VERSION 5.7 ;
  NOWIREEXTENSIONATPIN ON ;
  DIVIDERCHAR "/" ;
  BUSBITCHARS "[]" ;
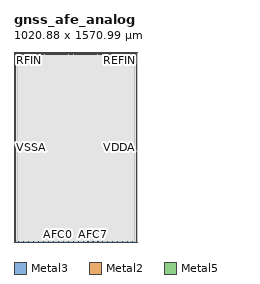
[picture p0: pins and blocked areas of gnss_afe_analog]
MACRO gnss_afe_analog
  CLASS BLOCK ;
  FOREIGN gnss_afe_analog ;
  ORIGIN 0.000 0.000 ;
  SIZE 1020.880 BY 1570.995 ;
  PIN VSSA
    DIRECTION INOUT ;
    USE GROUND ;
    PORT
      LAYER Metal3 ;
        RECT 6.000 6.000 9.000 1564.995 ;
    END
    PORT
      LAYER Metal2 ;
        RECT 431.640 1564.895 441.140 1570.995 ;
    END
    PORT
      LAYER Metal2 ;
        RECT 418.490 1564.895 428.740 1570.995 ;
    END
    PORT
      LAYER Metal2 ;
        RECT 406.640 1564.895 416.890 1570.995 ;
    END
    PORT
      LAYER Metal2 ;
        RECT 393.110 1564.895 403.360 1570.995 ;
    END
    PORT
      LAYER Metal2 ;
        RECT 381.260 1564.895 391.510 1570.995 ;
    END
    PORT
      LAYER Metal2 ;
        RECT 368.860 1564.895 378.360 1570.995 ;
    END
    PORT
      LAYER Metal2 ;
        RECT 223.640 1564.895 233.140 1570.995 ;
    END
    PORT
      LAYER Metal2 ;
        RECT 210.490 1564.895 220.740 1570.995 ;
    END
    PORT
      LAYER Metal2 ;
        RECT 198.640 1564.895 208.890 1570.995 ;
    END
    PORT
      LAYER Metal2 ;
        RECT 185.110 1564.895 195.360 1570.995 ;
    END
    PORT
      LAYER Metal2 ;
        RECT 173.260 1564.895 183.510 1570.995 ;
    END
    PORT
      LAYER Metal2 ;
        RECT 160.860 1564.895 170.360 1570.995 ;
    END
    PORT
      LAYER Metal2 ;
        RECT 15.640 1564.895 25.140 1570.995 ;
    END
    PORT
      LAYER Metal2 ;
        RECT 6.500 1564.895 12.740 1570.995 ;
    END
    PORT
      LAYER Metal5 ;
        RECT 6.000 1560.995 1014.880 1564.995 ;
    END
  END VSSA
  PIN VDDA
    DIRECTION INOUT ;
    USE POWER ;
    PORT
      LAYER Metal3 ;
        RECT 1011.880 6.000 1014.880 1564.995 ;
    END
    PORT
      LAYER Metal2 ;
        RECT 327.640 1553.895 337.140 1570.995 ;
    END
    PORT
      LAYER Metal2 ;
        RECT 314.490 1553.895 324.740 1570.995 ;
    END
    PORT
      LAYER Metal2 ;
        RECT 302.640 1553.895 312.890 1570.995 ;
    END
    PORT
      LAYER Metal2 ;
        RECT 289.110 1553.895 299.360 1570.995 ;
    END
    PORT
      LAYER Metal2 ;
        RECT 277.260 1553.895 287.510 1570.995 ;
    END
    PORT
      LAYER Metal2 ;
        RECT 264.860 1553.895 274.360 1570.995 ;
    END
    PORT
      LAYER Metal5 ;
        RECT 6.000 1549.995 45.500 1553.995 ;
    END
    PORT
      LAYER Metal5 ;
        RECT 56.500 1549.995 85.500 1553.995 ;
    END
    PORT
      LAYER Metal5 ;
        RECT 96.500 1549.995 125.500 1553.995 ;
    END
    PORT
      LAYER Metal5 ;
        RECT 136.500 1549.995 165.500 1553.995 ;
    END
    PORT
      LAYER Metal5 ;
        RECT 176.500 1549.995 205.500 1553.995 ;
    END
    PORT
      LAYER Metal5 ;
        RECT 216.500 1549.995 245.500 1553.995 ;
    END
    PORT
      LAYER Metal5 ;
        RECT 256.500 1549.995 285.500 1553.995 ;
    END
    PORT
      LAYER Metal5 ;
        RECT 296.500 1549.995 325.500 1553.995 ;
    END
    PORT
      LAYER Metal5 ;
        RECT 336.500 1549.995 365.500 1553.995 ;
    END
    PORT
      LAYER Metal5 ;
        RECT 376.500 1549.995 405.500 1553.995 ;
    END
    PORT
      LAYER Metal5 ;
        RECT 416.500 1549.995 445.500 1553.995 ;
    END
    PORT
      LAYER Metal5 ;
        RECT 456.500 1549.995 485.500 1553.995 ;
    END
    PORT
      LAYER Metal5 ;
        RECT 496.500 1549.995 525.500 1553.995 ;
    END
    PORT
      LAYER Metal5 ;
        RECT 536.500 1549.995 565.500 1553.995 ;
    END
    PORT
      LAYER Metal5 ;
        RECT 576.500 1549.995 605.500 1553.995 ;
    END
    PORT
      LAYER Metal5 ;
        RECT 616.500 1549.995 645.500 1553.995 ;
    END
    PORT
      LAYER Metal5 ;
        RECT 656.500 1549.995 665.500 1553.995 ;
    END
    PORT
      LAYER Metal5 ;
        RECT 676.500 1549.995 685.500 1553.995 ;
    END
    PORT
      LAYER Metal5 ;
        RECT 696.500 1549.995 725.500 1553.995 ;
    END
    PORT
      LAYER Metal5 ;
        RECT 736.500 1549.995 745.500 1553.995 ;
    END
    PORT
      LAYER Metal5 ;
        RECT 756.500 1549.995 765.500 1553.995 ;
    END
    PORT
      LAYER Metal5 ;
        RECT 776.500 1549.995 805.500 1553.995 ;
    END
    PORT
      LAYER Metal5 ;
        RECT 816.500 1549.995 825.500 1553.995 ;
    END
    PORT
      LAYER Metal5 ;
        RECT 836.500 1549.995 845.500 1553.995 ;
    END
    PORT
      LAYER Metal5 ;
        RECT 856.500 1549.995 885.500 1553.995 ;
    END
    PORT
      LAYER Metal5 ;
        RECT 896.500 1549.995 905.500 1553.995 ;
    END
    PORT
      LAYER Metal5 ;
        RECT 916.500 1549.995 925.500 1553.995 ;
    END
    PORT
      LAYER Metal5 ;
        RECT 936.500 1549.995 965.500 1553.995 ;
    END
    PORT
      LAYER Metal5 ;
        RECT 976.500 1549.995 1014.880 1553.995 ;
    END
  END VDDA
  PIN RFIN
    DIRECTION INOUT ;
    USE SIGNAL ;
    ANTENNADIFFAREA 33.599998 ;
    PORT
      LAYER Metal2 ;
        RECT 70.840 1568.995 115.160 1570.995 ;
    END
  END RFIN
  PIN VDDV
    DIRECTION INOUT ;
    USE POWER ;
    PORT
      LAYER Metal2 ;
        RECT 535.640 1559.395 545.140 1570.995 ;
    END
    PORT
      LAYER Metal2 ;
        RECT 522.490 1559.395 532.740 1570.995 ;
    END
    PORT
      LAYER Metal2 ;
        RECT 510.640 1559.395 520.890 1570.995 ;
    END
    PORT
      LAYER Metal2 ;
        RECT 497.110 1559.395 507.360 1570.995 ;
    END
    PORT
      LAYER Metal2 ;
        RECT 485.260 1559.395 495.510 1570.995 ;
    END
    PORT
      LAYER Metal2 ;
        RECT 472.860 1559.395 482.360 1570.995 ;
    END
    PORT
      LAYER Metal5 ;
        RECT 6.000 1555.495 45.500 1559.495 ;
    END
    PORT
      LAYER Metal5 ;
        RECT 56.500 1555.495 85.500 1559.495 ;
    END
    PORT
      LAYER Metal5 ;
        RECT 96.500 1555.495 125.500 1559.495 ;
    END
    PORT
      LAYER Metal5 ;
        RECT 136.500 1555.495 165.500 1559.495 ;
    END
    PORT
      LAYER Metal5 ;
        RECT 176.500 1555.495 205.500 1559.495 ;
    END
    PORT
      LAYER Metal5 ;
        RECT 216.500 1555.495 245.500 1559.495 ;
    END
    PORT
      LAYER Metal5 ;
        RECT 256.500 1555.495 285.500 1559.495 ;
    END
    PORT
      LAYER Metal5 ;
        RECT 296.500 1555.495 325.500 1559.495 ;
    END
    PORT
      LAYER Metal5 ;
        RECT 336.500 1555.495 365.500 1559.495 ;
    END
    PORT
      LAYER Metal5 ;
        RECT 376.500 1555.495 405.500 1559.495 ;
    END
    PORT
      LAYER Metal5 ;
        RECT 416.500 1555.495 445.500 1559.495 ;
    END
    PORT
      LAYER Metal5 ;
        RECT 456.500 1555.495 485.500 1559.495 ;
    END
    PORT
      LAYER Metal5 ;
        RECT 496.500 1555.495 525.500 1559.495 ;
    END
    PORT
      LAYER Metal5 ;
        RECT 536.500 1555.495 565.500 1559.495 ;
    END
    PORT
      LAYER Metal5 ;
        RECT 576.500 1555.495 605.500 1559.495 ;
    END
    PORT
      LAYER Metal5 ;
        RECT 616.500 1555.495 645.500 1559.495 ;
    END
    PORT
      LAYER Metal5 ;
        RECT 656.500 1555.495 685.500 1559.495 ;
    END
    PORT
      LAYER Metal5 ;
        RECT 696.500 1555.495 725.500 1559.495 ;
    END
    PORT
      LAYER Metal5 ;
        RECT 736.500 1555.495 765.500 1559.495 ;
    END
    PORT
      LAYER Metal5 ;
        RECT 776.500 1555.495 805.500 1559.495 ;
    END
    PORT
      LAYER Metal5 ;
        RECT 816.500 1555.495 845.500 1559.495 ;
    END
    PORT
      LAYER Metal5 ;
        RECT 856.500 1555.495 885.500 1559.495 ;
    END
    PORT
      LAYER Metal5 ;
        RECT 896.500 1555.495 925.500 1559.495 ;
    END
    PORT
      LAYER Metal5 ;
        RECT 936.500 1555.495 965.500 1559.495 ;
    END
    PORT
      LAYER Metal5 ;
        RECT 976.500 1555.495 1014.880 1559.495 ;
    END
  END VDDV
  PIN REFIN
    DIRECTION INOUT ;
    USE SIGNAL ;
    PORT
      LAYER Metal2 ;
        RECT 1011.500 1568.995 1019.880 1570.995 ;
    END
  END REFIN
  PIN AFCOUT
    DIRECTION INOUT ;
    USE SIGNAL ;
    PORT
      LAYER Metal2 ;
        RECT 915.000 1568.995 925.000 1570.995 ;
    END
  END AFCOUT
  PIN VCTRL
    DIRECTION INOUT ;
    USE SIGNAL ;
    PORT
      LAYER Metal2 ;
        RECT 603.000 1568.995 613.000 1570.995 ;
    END
  END VCTRL
  PIN IG1A
    DIRECTION INOUT ;
    USE SIGNAL ;
    ANTENNAGATEAREA 22.719999 ;
    PORT
      LAYER Metal3 ;
        RECT 39.800 -0.100 40.800 0.900 ;
    END
  END IG1A
  PIN IG1B
    DIRECTION INOUT ;
    USE SIGNAL ;
    ANTENNAGATEAREA 22.719999 ;
    PORT
      LAYER Metal3 ;
        RECT 80.400 -0.100 81.400 0.900 ;
    END
  END IG1B
  PIN IG2A
    DIRECTION INOUT ;
    USE SIGNAL ;
    ANTENNAGATEAREA 22.719999 ;
    PORT
      LAYER Metal3 ;
        RECT 121.700 -0.100 122.700 0.900 ;
    END
  END IG2A
  PIN IG2B
    DIRECTION INOUT ;
    USE SIGNAL ;
    ANTENNAGATEAREA 22.719999 ;
    PORT
      LAYER Metal3 ;
        RECT 162.300 -0.100 163.300 0.900 ;
    END
  END IG2B
  PIN IG3A
    DIRECTION INOUT ;
    USE SIGNAL ;
    ANTENNAGATEAREA 22.719999 ;
    PORT
      LAYER Metal3 ;
        RECT 202.900 -0.100 203.900 0.900 ;
    END
  END IG3A
  PIN IG3B
    DIRECTION INOUT ;
    USE SIGNAL ;
    ANTENNAGATEAREA 22.719999 ;
    PORT
      LAYER Metal3 ;
        RECT 244.200 -0.100 245.200 0.900 ;
    END
  END IG3B
  PIN B0
    DIRECTION INOUT ;
    USE SIGNAL ;
    PORT
      LAYER Metal3 ;
        RECT 284.800 -0.100 285.800 0.900 ;
    END
  END B0
  PIN B1
    DIRECTION INOUT ;
    USE SIGNAL ;
    PORT
      LAYER Metal3 ;
        RECT 325.400 -0.100 326.400 0.900 ;
    END
  END B1
  PIN AFC0
    DIRECTION INOUT ;
    USE SIGNAL ;
    ANTENNAGATEAREA 0.840000 ;
    PORT
      LAYER Metal3 ;
        RECT 366.700 -0.100 367.700 0.900 ;
    END
  END AFC0
  PIN AFC1
    DIRECTION INOUT ;
    USE SIGNAL ;
    ANTENNAGATEAREA 0.840000 ;
    PORT
      LAYER Metal3 ;
        RECT 407.300 -0.100 408.300 0.900 ;
    END
  END AFC1
  PIN AFC2
    DIRECTION INOUT ;
    USE SIGNAL ;
    ANTENNAGATEAREA 0.840000 ;
    PORT
      LAYER Metal3 ;
        RECT 447.900 -0.100 448.900 0.900 ;
    END
  END AFC2
  PIN AFC3
    DIRECTION INOUT ;
    USE SIGNAL ;
    ANTENNAGATEAREA 0.840000 ;
    PORT
      LAYER Metal3 ;
        RECT 489.200 -0.100 490.200 0.900 ;
    END
  END AFC3
  PIN AFC4
    DIRECTION INOUT ;
    USE SIGNAL ;
    ANTENNAGATEAREA 0.840000 ;
    PORT
      LAYER Metal3 ;
        RECT 529.800 -0.100 530.800 0.900 ;
    END
  END AFC4
  PIN AFC5
    DIRECTION INOUT ;
    USE SIGNAL ;
    ANTENNAGATEAREA 0.840000 ;
    PORT
      LAYER Metal3 ;
        RECT 571.100 -0.100 572.100 0.900 ;
    END
  END AFC5
  PIN AFC6
    DIRECTION INOUT ;
    USE SIGNAL ;
    ANTENNAGATEAREA 0.840000 ;
    PORT
      LAYER Metal3 ;
        RECT 611.700 -0.100 612.700 0.900 ;
    END
  END AFC6
  PIN AFC7
    DIRECTION INOUT ;
    USE SIGNAL ;
    ANTENNAGATEAREA 0.840000 ;
    PORT
      LAYER Metal3 ;
        RECT 652.300 -0.100 653.300 0.900 ;
    END
  END AFC7
  PIN ICP2
    DIRECTION INOUT ;
    USE SIGNAL ;
    ANTENNAGATEAREA 1.960000 ;
    PORT
      LAYER Metal3 ;
        RECT 693.600 -0.100 694.600 0.900 ;
    END
  END ICP2
  PIN BWK
    DIRECTION INOUT ;
    USE SIGNAL ;
    ANTENNAGATEAREA 0.840000 ;
    ANTENNADIFFAREA 0.445000 ;
    PORT
      LAYER Metal3 ;
        RECT 734.200 -0.100 735.200 0.900 ;
    END
  END BWK
  PIN BWN
    DIRECTION INOUT ;
    USE SIGNAL ;
    ANTENNAGATEAREA 0.840000 ;
    ANTENNADIFFAREA 0.445000 ;
    PORT
      LAYER Metal3 ;
        RECT 774.800 -0.100 775.800 0.900 ;
    END
  END BWN
  PIN I_SIGN
    DIRECTION INOUT ;
    USE SIGNAL ;
    ANTENNAGATEAREA 1.400000 ;
    ANTENNADIFFAREA 2.670000 ;
    PORT
      LAYER Metal3 ;
        RECT 816.100 -0.100 817.100 0.900 ;
    END
  END I_SIGN
  PIN I_MAG
    DIRECTION INOUT ;
    USE SIGNAL ;
    ANTENNADIFFAREA 2.670000 ;
    PORT
      LAYER Metal3 ;
        RECT 856.700 -0.100 857.700 0.900 ;
    END
  END I_MAG
  PIN Q_SIGN
    DIRECTION INOUT ;
    USE SIGNAL ;
    ANTENNAGATEAREA 1.400000 ;
    ANTENNADIFFAREA 2.670000 ;
    PORT
      LAYER Metal3 ;
        RECT 897.300 -0.100 898.300 0.900 ;
    END
  END Q_SIGN
  PIN Q_MAG
    DIRECTION INOUT ;
    USE SIGNAL ;
    ANTENNADIFFAREA 2.670000 ;
    PORT
      LAYER Metal3 ;
        RECT 938.600 -0.100 939.600 0.900 ;
    END
  END Q_MAG
  PIN CLKOUT
    DIRECTION INOUT ;
    USE SIGNAL ;
    ANTENNADIFFAREA 4.770000 ;
    PORT
      LAYER Metal3 ;
        RECT 979.200 -0.100 980.200 0.900 ;
    END
  END CLKOUT
  OBS
      LAYER Nwell ;
        RECT 22.860 18.360 999.180 1542.295 ;
      LAYER Metal1 ;
        RECT 23.045 18.545 998.995 1542.110 ;
      LAYER Metal2 ;
        RECT 13.040 1564.595 15.340 1569.290 ;
        RECT 25.440 1568.695 70.540 1569.290 ;
        RECT 115.460 1568.695 160.560 1569.290 ;
        RECT 25.440 1564.595 160.560 1568.695 ;
        RECT 170.660 1564.595 172.960 1569.290 ;
        RECT 183.810 1564.595 184.810 1569.290 ;
        RECT 195.660 1564.595 198.340 1569.290 ;
        RECT 209.190 1564.595 210.190 1569.290 ;
        RECT 221.040 1564.595 223.340 1569.290 ;
        RECT 233.440 1564.595 264.560 1569.290 ;
        RECT 6.500 1553.595 264.560 1564.595 ;
        RECT 274.660 1553.595 276.960 1569.290 ;
        RECT 287.810 1553.595 288.810 1569.290 ;
        RECT 299.660 1553.595 302.340 1569.290 ;
        RECT 313.190 1553.595 314.190 1569.290 ;
        RECT 325.040 1553.595 327.340 1569.290 ;
        RECT 337.440 1564.595 368.560 1569.290 ;
        RECT 378.660 1564.595 380.960 1569.290 ;
        RECT 391.810 1564.595 392.810 1569.290 ;
        RECT 403.660 1564.595 406.340 1569.290 ;
        RECT 417.190 1564.595 418.190 1569.290 ;
        RECT 429.040 1564.595 431.340 1569.290 ;
        RECT 441.440 1564.595 472.560 1569.290 ;
        RECT 337.440 1559.095 472.560 1564.595 ;
        RECT 482.660 1559.095 484.960 1569.290 ;
        RECT 495.810 1559.095 496.810 1569.290 ;
        RECT 507.660 1559.095 510.340 1569.290 ;
        RECT 521.190 1559.095 522.190 1569.290 ;
        RECT 533.040 1559.095 535.340 1569.290 ;
        RECT 545.440 1568.695 602.700 1569.290 ;
        RECT 613.300 1568.695 914.700 1569.290 ;
        RECT 925.300 1568.695 1011.200 1569.290 ;
        RECT 545.440 1559.095 1019.880 1568.695 ;
        RECT 337.440 1553.595 1019.880 1559.095 ;
        RECT 6.500 0.210 1019.880 1553.595 ;
      LAYER Metal3 ;
        RECT 9.000 1565.295 1012.090 1570.650 ;
        RECT 9.300 5.700 1011.580 1565.295 ;
        RECT 9.000 1.200 1012.090 5.700 ;
        RECT 9.000 0.210 39.500 1.200 ;
        RECT 41.100 0.210 80.100 1.200 ;
        RECT 81.700 0.210 121.400 1.200 ;
        RECT 123.000 0.210 162.000 1.200 ;
        RECT 163.600 0.210 202.600 1.200 ;
        RECT 204.200 0.210 243.900 1.200 ;
        RECT 245.500 0.210 284.500 1.200 ;
        RECT 286.100 0.210 325.100 1.200 ;
        RECT 326.700 0.210 366.400 1.200 ;
        RECT 368.000 0.210 407.000 1.200 ;
        RECT 408.600 0.210 447.600 1.200 ;
        RECT 449.200 0.210 488.900 1.200 ;
        RECT 490.500 0.210 529.500 1.200 ;
        RECT 531.100 0.210 570.800 1.200 ;
        RECT 572.400 0.210 611.400 1.200 ;
        RECT 613.000 0.210 652.000 1.200 ;
        RECT 653.600 0.210 693.300 1.200 ;
        RECT 694.900 0.210 733.900 1.200 ;
        RECT 735.500 0.210 774.500 1.200 ;
        RECT 776.100 0.210 815.800 1.200 ;
        RECT 817.400 0.210 856.400 1.200 ;
        RECT 858.000 0.210 897.000 1.200 ;
        RECT 898.600 0.210 938.300 1.200 ;
        RECT 939.900 0.210 978.900 1.200 ;
        RECT 980.500 0.210 1012.090 1.200 ;
      LAYER Metal4 ;
        RECT 6.000 1.610 1014.880 1569.290 ;
      LAYER Metal5 ;
        RECT 26.000 1560.095 996.000 1560.395 ;
        RECT 46.100 1554.895 55.900 1560.095 ;
        RECT 86.100 1554.895 95.900 1560.095 ;
        RECT 126.100 1554.895 135.900 1560.095 ;
        RECT 166.100 1554.895 175.900 1560.095 ;
        RECT 206.100 1554.895 215.900 1560.095 ;
        RECT 246.100 1554.895 255.900 1560.095 ;
        RECT 286.100 1554.895 295.900 1560.095 ;
        RECT 326.100 1554.895 335.900 1560.095 ;
        RECT 366.100 1554.895 375.900 1560.095 ;
        RECT 406.100 1554.895 415.900 1560.095 ;
        RECT 446.100 1554.895 455.900 1560.095 ;
        RECT 486.100 1554.895 495.900 1560.095 ;
        RECT 526.100 1554.895 535.900 1560.095 ;
        RECT 566.100 1554.895 575.900 1560.095 ;
        RECT 606.100 1554.895 615.900 1560.095 ;
        RECT 646.100 1554.895 655.900 1560.095 ;
        RECT 686.100 1554.895 695.900 1560.095 ;
        RECT 726.100 1554.895 735.900 1560.095 ;
        RECT 766.100 1554.895 775.900 1560.095 ;
        RECT 806.100 1554.895 815.900 1560.095 ;
        RECT 846.100 1554.895 855.900 1560.095 ;
        RECT 886.100 1554.895 895.900 1560.095 ;
        RECT 926.100 1554.895 935.900 1560.095 ;
        RECT 966.100 1554.895 975.900 1560.095 ;
        RECT 26.000 1554.595 996.000 1554.895 ;
        RECT 46.100 1549.395 55.900 1554.595 ;
        RECT 86.100 1549.395 95.900 1554.595 ;
        RECT 126.100 1549.395 135.900 1554.595 ;
        RECT 166.100 1549.395 175.900 1554.595 ;
        RECT 206.100 1549.395 215.900 1554.595 ;
        RECT 246.100 1549.395 255.900 1554.595 ;
        RECT 286.100 1549.395 295.900 1554.595 ;
        RECT 326.100 1549.395 335.900 1554.595 ;
        RECT 366.100 1549.395 375.900 1554.595 ;
        RECT 406.100 1549.395 415.900 1554.595 ;
        RECT 446.100 1549.395 455.900 1554.595 ;
        RECT 486.100 1549.395 495.900 1554.595 ;
        RECT 526.100 1549.395 535.900 1554.595 ;
        RECT 566.100 1549.395 575.900 1554.595 ;
        RECT 606.100 1549.395 615.900 1554.595 ;
        RECT 646.100 1549.395 655.900 1554.595 ;
        RECT 666.100 1549.395 675.900 1554.595 ;
        RECT 686.100 1549.395 695.900 1554.595 ;
        RECT 726.100 1549.395 735.900 1554.595 ;
        RECT 746.100 1549.395 755.900 1554.595 ;
        RECT 766.100 1549.395 775.900 1554.595 ;
        RECT 806.100 1549.395 815.900 1554.595 ;
        RECT 826.100 1549.395 835.900 1554.595 ;
        RECT 846.100 1549.395 855.900 1554.595 ;
        RECT 886.100 1549.395 895.900 1554.595 ;
        RECT 906.100 1549.395 915.900 1554.595 ;
        RECT 926.100 1549.395 935.900 1554.595 ;
        RECT 966.100 1549.395 975.900 1554.595 ;
        RECT 26.000 6.000 996.000 1549.395 ;
  END
END gnss_afe_analog
END LIBRARY

